VERSION 5.7 ;
  NOWIREEXTENSIONATPIN ON ;
  DIVIDERCHAR "/" ;
  BUSBITCHARS "[]" ;
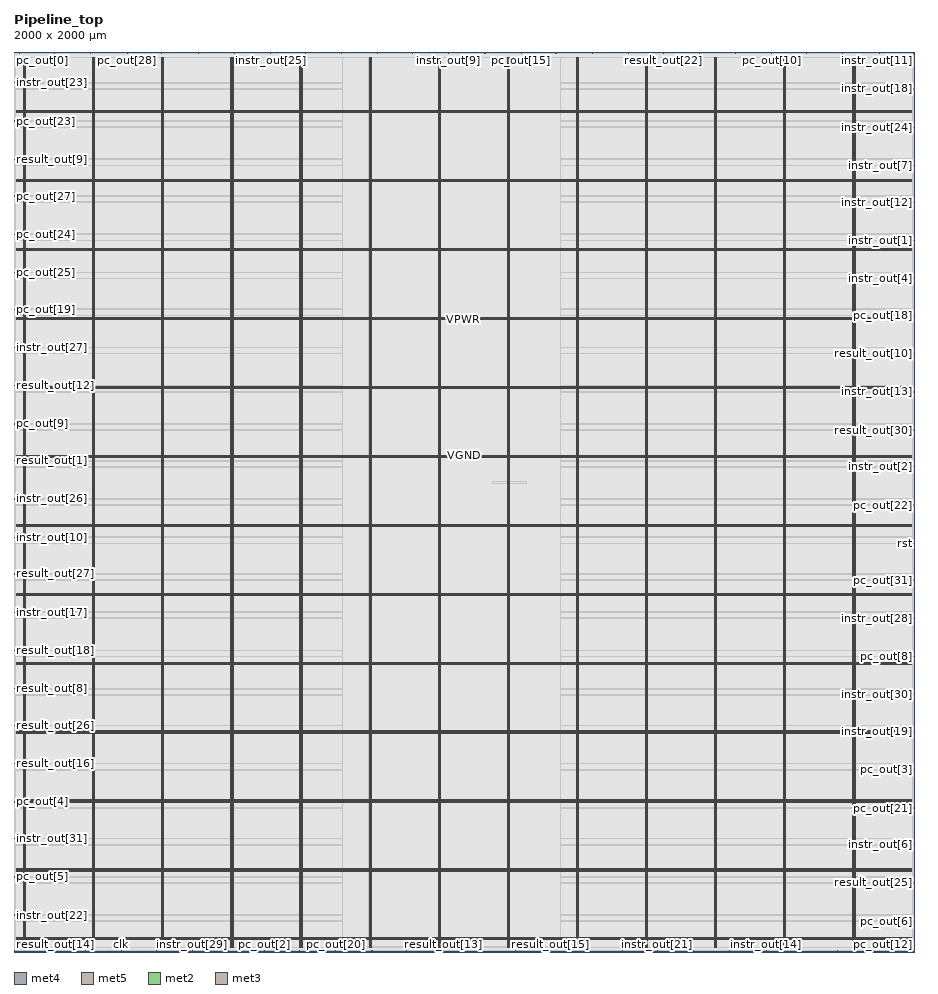
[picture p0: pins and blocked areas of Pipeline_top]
MACRO Pipeline_top
  CLASS BLOCK ;
  FOREIGN Pipeline_top ;
  ORIGIN 0.000 0.000 ;
  SIZE 2000.000 BY 2000.000 ;
  PIN VGND
    DIRECTION INOUT ;
    USE GROUND ;
    PORT
      LAYER met4 ;
        RECT 24.340 10.640 25.940 1988.560 ;
    END
    PORT
      LAYER met4 ;
        RECT 177.940 10.640 179.540 1988.560 ;
    END
    PORT
      LAYER met4 ;
        RECT 331.540 10.640 333.140 1988.560 ;
    END
    PORT
      LAYER met4 ;
        RECT 485.140 10.640 486.740 1988.560 ;
    END
    PORT
      LAYER met4 ;
        RECT 638.740 10.640 640.340 1988.560 ;
    END
    PORT
      LAYER met4 ;
        RECT 792.340 10.640 793.940 1988.560 ;
    END
    PORT
      LAYER met4 ;
        RECT 945.940 10.640 947.540 1988.560 ;
    END
    PORT
      LAYER met4 ;
        RECT 1099.540 10.640 1101.140 1988.560 ;
    END
    PORT
      LAYER met4 ;
        RECT 1253.140 10.640 1254.740 1988.560 ;
    END
    PORT
      LAYER met4 ;
        RECT 1406.740 10.640 1408.340 1988.560 ;
    END
    PORT
      LAYER met4 ;
        RECT 1560.340 10.640 1561.940 1988.560 ;
    END
    PORT
      LAYER met4 ;
        RECT 1713.940 10.640 1715.540 1988.560 ;
    END
    PORT
      LAYER met4 ;
        RECT 1867.540 10.640 1869.140 1988.560 ;
    END
    PORT
      LAYER met5 ;
        RECT 5.280 30.030 1994.340 31.630 ;
    END
    PORT
      LAYER met5 ;
        RECT 5.280 183.210 1994.340 184.810 ;
    END
    PORT
      LAYER met5 ;
        RECT 5.280 336.390 1994.340 337.990 ;
    END
    PORT
      LAYER met5 ;
        RECT 5.280 489.570 1994.340 491.170 ;
    END
    PORT
      LAYER met5 ;
        RECT 5.280 642.750 1994.340 644.350 ;
    END
    PORT
      LAYER met5 ;
        RECT 5.280 795.930 1994.340 797.530 ;
    END
    PORT
      LAYER met5 ;
        RECT 5.280 949.110 1994.340 950.710 ;
    END
    PORT
      LAYER met5 ;
        RECT 5.280 1102.290 1994.340 1103.890 ;
    END
    PORT
      LAYER met5 ;
        RECT 5.280 1255.470 1994.340 1257.070 ;
    END
    PORT
      LAYER met5 ;
        RECT 5.280 1408.650 1994.340 1410.250 ;
    END
    PORT
      LAYER met5 ;
        RECT 5.280 1561.830 1994.340 1563.430 ;
    END
    PORT
      LAYER met5 ;
        RECT 5.280 1715.010 1994.340 1716.610 ;
    END
    PORT
      LAYER met5 ;
        RECT 5.280 1868.190 1994.340 1869.790 ;
    END
  END VGND
  PIN VPWR
    DIRECTION INOUT ;
    USE POWER ;
    PORT
      LAYER met4 ;
        RECT 21.040 10.640 22.640 1988.560 ;
    END
    PORT
      LAYER met4 ;
        RECT 174.640 10.640 176.240 1988.560 ;
    END
    PORT
      LAYER met4 ;
        RECT 328.240 10.640 329.840 1988.560 ;
    END
    PORT
      LAYER met4 ;
        RECT 481.840 10.640 483.440 1988.560 ;
    END
    PORT
      LAYER met4 ;
        RECT 635.440 10.640 637.040 1988.560 ;
    END
    PORT
      LAYER met4 ;
        RECT 789.040 10.640 790.640 1988.560 ;
    END
    PORT
      LAYER met4 ;
        RECT 942.640 10.640 944.240 1988.560 ;
    END
    PORT
      LAYER met4 ;
        RECT 1096.240 10.640 1097.840 1988.560 ;
    END
    PORT
      LAYER met4 ;
        RECT 1249.840 10.640 1251.440 1988.560 ;
    END
    PORT
      LAYER met4 ;
        RECT 1403.440 10.640 1405.040 1988.560 ;
    END
    PORT
      LAYER met4 ;
        RECT 1557.040 10.640 1558.640 1988.560 ;
    END
    PORT
      LAYER met4 ;
        RECT 1710.640 10.640 1712.240 1988.560 ;
    END
    PORT
      LAYER met4 ;
        RECT 1864.240 10.640 1865.840 1988.560 ;
    END
    PORT
      LAYER met5 ;
        RECT 5.280 26.730 1994.340 28.330 ;
    END
    PORT
      LAYER met5 ;
        RECT 5.280 179.910 1994.340 181.510 ;
    END
    PORT
      LAYER met5 ;
        RECT 5.280 333.090 1994.340 334.690 ;
    END
    PORT
      LAYER met5 ;
        RECT 5.280 486.270 1994.340 487.870 ;
    END
    PORT
      LAYER met5 ;
        RECT 5.280 639.450 1994.340 641.050 ;
    END
    PORT
      LAYER met5 ;
        RECT 5.280 792.630 1994.340 794.230 ;
    END
    PORT
      LAYER met5 ;
        RECT 5.280 945.810 1994.340 947.410 ;
    END
    PORT
      LAYER met5 ;
        RECT 5.280 1098.990 1994.340 1100.590 ;
    END
    PORT
      LAYER met5 ;
        RECT 5.280 1252.170 1994.340 1253.770 ;
    END
    PORT
      LAYER met5 ;
        RECT 5.280 1405.350 1994.340 1406.950 ;
    END
    PORT
      LAYER met5 ;
        RECT 5.280 1558.530 1994.340 1560.130 ;
    END
    PORT
      LAYER met5 ;
        RECT 5.280 1711.710 1994.340 1713.310 ;
    END
    PORT
      LAYER met5 ;
        RECT 5.280 1864.890 1994.340 1866.490 ;
    END
  END VPWR
  PIN clk
    DIRECTION INPUT ;
    USE SIGNAL ;
    ANTENNAGATEAREA 1.286700 ;
    ANTENNADIFFAREA 0.434700 ;
    PORT
      LAYER met2 ;
        RECT 238.370 0.000 238.650 4.000 ;
    END
  END clk
  PIN instr_out[0]
    DIRECTION OUTPUT TRISTATE ;
    USE SIGNAL ;
    ANTENNADIFFAREA 0.795200 ;
    PORT
      LAYER met2 ;
        RECT 1365.370 1996.000 1365.650 2000.000 ;
    END
  END instr_out[0]
  PIN instr_out[10]
    DIRECTION OUTPUT TRISTATE ;
    USE SIGNAL ;
    ANTENNADIFFAREA 0.795200 ;
    PORT
      LAYER met3 ;
        RECT 0.000 921.440 4.000 922.040 ;
    END
  END instr_out[10]
  PIN instr_out[11]
    DIRECTION OUTPUT TRISTATE ;
    USE SIGNAL ;
    PORT
      LAYER met2 ;
        RECT 1922.430 1996.000 1922.710 2000.000 ;
    END
  END instr_out[11]
  PIN instr_out[12]
    DIRECTION OUTPUT TRISTATE ;
    USE SIGNAL ;
    PORT
      LAYER met3 ;
        RECT 1996.000 1666.040 2000.000 1666.640 ;
    END
  END instr_out[12]
  PIN instr_out[13]
    DIRECTION OUTPUT TRISTATE ;
    USE SIGNAL ;
    ANTENNADIFFAREA 0.445500 ;
    PORT
      LAYER met3 ;
        RECT 1996.000 1244.440 2000.000 1245.040 ;
    END
  END instr_out[13]
  PIN instr_out[14]
    DIRECTION OUTPUT TRISTATE ;
    USE SIGNAL ;
    PORT
      LAYER met2 ;
        RECT 1671.270 0.000 1671.550 4.000 ;
    END
  END instr_out[14]
  PIN instr_out[15]
    DIRECTION OUTPUT TRISTATE ;
    USE SIGNAL ;
    ANTENNADIFFAREA 0.795200 ;
    PORT
      LAYER met2 ;
        RECT 727.810 1996.000 728.090 2000.000 ;
    END
  END instr_out[15]
  PIN instr_out[16]
    DIRECTION OUTPUT TRISTATE ;
    USE SIGNAL ;
    PORT
      LAYER met2 ;
        RECT 808.310 1996.000 808.590 2000.000 ;
    END
  END instr_out[16]
  PIN instr_out[17]
    DIRECTION OUTPUT TRISTATE ;
    USE SIGNAL ;
    ANTENNADIFFAREA 0.795200 ;
    PORT
      LAYER met3 ;
        RECT 0.000 754.840 4.000 755.440 ;
    END
  END instr_out[17]
  PIN instr_out[18]
    DIRECTION OUTPUT TRISTATE ;
    USE SIGNAL ;
    ANTENNADIFFAREA 0.795200 ;
    PORT
      LAYER met3 ;
        RECT 1996.000 1917.640 2000.000 1918.240 ;
    END
  END instr_out[18]
  PIN instr_out[19]
    DIRECTION OUTPUT TRISTATE ;
    USE SIGNAL ;
    PORT
      LAYER met3 ;
        RECT 1996.000 489.640 2000.000 490.240 ;
    END
  END instr_out[19]
  PIN instr_out[1]
    DIRECTION OUTPUT TRISTATE ;
    USE SIGNAL ;
    ANTENNADIFFAREA 0.445500 ;
    PORT
      LAYER met3 ;
        RECT 1996.000 1581.040 2000.000 1581.640 ;
    END
  END instr_out[1]
  PIN instr_out[20]
    DIRECTION OUTPUT TRISTATE ;
    USE SIGNAL ;
    ANTENNADIFFAREA 0.795200 ;
    PORT
      LAYER met2 ;
        RECT 647.310 1996.000 647.590 2000.000 ;
    END
  END instr_out[20]
  PIN instr_out[21]
    DIRECTION OUTPUT TRISTATE ;
    USE SIGNAL ;
    ANTENNADIFFAREA 0.795200 ;
    PORT
      LAYER met2 ;
        RECT 1429.770 0.000 1430.050 4.000 ;
    END
  END instr_out[21]
  PIN instr_out[22]
    DIRECTION OUTPUT TRISTATE ;
    USE SIGNAL ;
    ANTENNADIFFAREA 0.795200 ;
    PORT
      LAYER met3 ;
        RECT 0.000 81.640 4.000 82.240 ;
    END
  END instr_out[22]
  PIN instr_out[23]
    DIRECTION OUTPUT TRISTATE ;
    USE SIGNAL ;
    ANTENNADIFFAREA 0.795200 ;
    PORT
      LAYER met3 ;
        RECT 0.000 1931.240 4.000 1931.840 ;
    END
  END instr_out[23]
  PIN instr_out[24]
    DIRECTION OUTPUT TRISTATE ;
    USE SIGNAL ;
    PORT
      LAYER met3 ;
        RECT 1996.000 1832.640 2000.000 1833.240 ;
    END
  END instr_out[24]
  PIN instr_out[25]
    DIRECTION OUTPUT TRISTATE ;
    USE SIGNAL ;
    PORT
      LAYER met2 ;
        RECT 570.030 1996.000 570.310 2000.000 ;
    END
  END instr_out[25]
  PIN instr_out[26]
    DIRECTION OUTPUT TRISTATE ;
    USE SIGNAL ;
    PORT
      LAYER met3 ;
        RECT 0.000 1006.440 4.000 1007.040 ;
    END
  END instr_out[26]
  PIN instr_out[27]
    DIRECTION OUTPUT TRISTATE ;
    USE SIGNAL ;
    PORT
      LAYER met3 ;
        RECT 0.000 1343.040 4.000 1343.640 ;
    END
  END instr_out[27]
  PIN instr_out[28]
    DIRECTION OUTPUT TRISTATE ;
    USE SIGNAL ;
    PORT
      LAYER met3 ;
        RECT 1996.000 741.240 2000.000 741.840 ;
    END
  END instr_out[28]
  PIN instr_out[29]
    DIRECTION OUTPUT TRISTATE ;
    USE SIGNAL ;
    PORT
      LAYER met2 ;
        RECT 396.150 0.000 396.430 4.000 ;
    END
  END instr_out[29]
  PIN instr_out[2]
    DIRECTION OUTPUT TRISTATE ;
    USE SIGNAL ;
    PORT
      LAYER met3 ;
        RECT 1996.000 1077.840 2000.000 1078.440 ;
    END
  END instr_out[2]
  PIN instr_out[30]
    DIRECTION OUTPUT TRISTATE ;
    USE SIGNAL ;
    PORT
      LAYER met3 ;
        RECT 1996.000 571.240 2000.000 571.840 ;
    END
  END instr_out[30]
  PIN instr_out[31]
    DIRECTION OUTPUT TRISTATE ;
    USE SIGNAL ;
    PORT
      LAYER met3 ;
        RECT 0.000 251.640 4.000 252.240 ;
    END
  END instr_out[31]
  PIN instr_out[3]
    DIRECTION OUTPUT TRISTATE ;
    USE SIGNAL ;
    PORT
      LAYER met2 ;
        RECT 795.430 0.000 795.710 4.000 ;
    END
  END instr_out[3]
  PIN instr_out[4]
    DIRECTION OUTPUT TRISTATE ;
    USE SIGNAL ;
    ANTENNADIFFAREA 0.445500 ;
    PORT
      LAYER met3 ;
        RECT 1996.000 1496.040 2000.000 1496.640 ;
    END
  END instr_out[4]
  PIN instr_out[5]
    DIRECTION OUTPUT TRISTATE ;
    USE SIGNAL ;
    ANTENNADIFFAREA 0.795200 ;
    PORT
      LAYER met2 ;
        RECT 1271.990 0.000 1272.270 4.000 ;
    END
  END instr_out[5]
  PIN instr_out[6]
    DIRECTION OUTPUT TRISTATE ;
    USE SIGNAL ;
    PORT
      LAYER met3 ;
        RECT 1996.000 238.040 2000.000 238.640 ;
    END
  END instr_out[6]
  PIN instr_out[7]
    DIRECTION OUTPUT TRISTATE ;
    USE SIGNAL ;
    ANTENNADIFFAREA 0.445500 ;
    PORT
      LAYER met3 ;
        RECT 1996.000 1747.640 2000.000 1748.240 ;
    END
  END instr_out[7]
  PIN instr_out[8]
    DIRECTION OUTPUT TRISTATE ;
    USE SIGNAL ;
    ANTENNADIFFAREA 0.795200 ;
    PORT
      LAYER met2 ;
        RECT 1284.870 1996.000 1285.150 2000.000 ;
    END
  END instr_out[8]
  PIN instr_out[9]
    DIRECTION OUTPUT TRISTATE ;
    USE SIGNAL ;
    ANTENNADIFFAREA 0.795200 ;
    PORT
      LAYER met2 ;
        RECT 966.090 1996.000 966.370 2000.000 ;
    END
  END instr_out[9]
  PIN pc_out[0]
    DIRECTION OUTPUT TRISTATE ;
    USE SIGNAL ;
    PORT
      LAYER met2 ;
        RECT 12.970 1996.000 13.250 2000.000 ;
    END
  END pc_out[0]
  PIN pc_out[10]
    DIRECTION OUTPUT TRISTATE ;
    USE SIGNAL ;
    ANTENNADIFFAREA 0.795200 ;
    PORT
      LAYER met2 ;
        RECT 1684.150 1996.000 1684.430 2000.000 ;
    END
  END pc_out[10]
  PIN pc_out[11]
    DIRECTION OUTPUT TRISTATE ;
    USE SIGNAL ;
    ANTENNADIFFAREA 0.795200 ;
    PORT
      LAYER met2 ;
        RECT 476.650 0.000 476.930 4.000 ;
    END
  END pc_out[11]
  PIN pc_out[12]
    DIRECTION OUTPUT TRISTATE ;
    USE SIGNAL ;
    ANTENNADIFFAREA 0.795200 ;
    PORT
      LAYER met2 ;
        RECT 1986.830 0.000 1987.110 4.000 ;
    END
  END pc_out[12]
  PIN pc_out[13]
    DIRECTION OUTPUT TRISTATE ;
    USE SIGNAL ;
    ANTENNADIFFAREA 0.795200 ;
    PORT
      LAYER met2 ;
        RECT 1829.050 0.000 1829.330 4.000 ;
    END
  END pc_out[13]
  PIN pc_out[14]
    DIRECTION OUTPUT TRISTATE ;
    USE SIGNAL ;
    ANTENNADIFFAREA 0.795200 ;
    PORT
      LAYER met2 ;
        RECT 885.590 1996.000 885.870 2000.000 ;
    END
  END pc_out[14]
  PIN pc_out[15]
    DIRECTION OUTPUT TRISTATE ;
    USE SIGNAL ;
    ANTENNADIFFAREA 0.795200 ;
    PORT
      LAYER met2 ;
        RECT 1127.090 1996.000 1127.370 2000.000 ;
    END
  END pc_out[15]
  PIN pc_out[16]
    DIRECTION OUTPUT TRISTATE ;
    USE SIGNAL ;
    ANTENNADIFFAREA 0.795200 ;
    PORT
      LAYER met2 ;
        RECT 1761.430 1996.000 1761.710 2000.000 ;
    END
  END pc_out[16]
  PIN pc_out[17]
    DIRECTION OUTPUT TRISTATE ;
    USE SIGNAL ;
    ANTENNADIFFAREA 0.795200 ;
    PORT
      LAYER met2 ;
        RECT 1909.550 0.000 1909.830 4.000 ;
    END
  END pc_out[17]
  PIN pc_out[18]
    DIRECTION OUTPUT TRISTATE ;
    USE SIGNAL ;
    ANTENNADIFFAREA 0.795200 ;
    PORT
      LAYER met3 ;
        RECT 1996.000 1414.440 2000.000 1415.040 ;
    END
  END pc_out[18]
  PIN pc_out[19]
    DIRECTION OUTPUT TRISTATE ;
    USE SIGNAL ;
    ANTENNADIFFAREA 0.795200 ;
    PORT
      LAYER met3 ;
        RECT 0.000 1428.040 4.000 1428.640 ;
    END
  END pc_out[19]
  PIN pc_out[1]
    DIRECTION OUTPUT TRISTATE ;
    USE SIGNAL ;
    PORT
      LAYER met2 ;
        RECT 1204.370 1996.000 1204.650 2000.000 ;
    END
  END pc_out[1]
  PIN pc_out[20]
    DIRECTION OUTPUT TRISTATE ;
    USE SIGNAL ;
    ANTENNADIFFAREA 0.795200 ;
    PORT
      LAYER met2 ;
        RECT 714.930 0.000 715.210 4.000 ;
    END
  END pc_out[20]
  PIN pc_out[21]
    DIRECTION OUTPUT TRISTATE ;
    USE SIGNAL ;
    ANTENNADIFFAREA 0.445500 ;
    PORT
      LAYER met3 ;
        RECT 1996.000 319.640 2000.000 320.240 ;
    END
  END pc_out[21]
  PIN pc_out[22]
    DIRECTION OUTPUT TRISTATE ;
    USE SIGNAL ;
    ANTENNADIFFAREA 0.795200 ;
    PORT
      LAYER met3 ;
        RECT 1996.000 992.840 2000.000 993.440 ;
    END
  END pc_out[22]
  PIN pc_out[23]
    DIRECTION OUTPUT TRISTATE ;
    USE SIGNAL ;
    ANTENNADIFFAREA 0.795200 ;
    PORT
      LAYER met3 ;
        RECT 0.000 1846.240 4.000 1846.840 ;
    END
  END pc_out[23]
  PIN pc_out[24]
    DIRECTION OUTPUT TRISTATE ;
    USE SIGNAL ;
    ANTENNADIFFAREA 0.795200 ;
    PORT
      LAYER met3 ;
        RECT 0.000 1594.640 4.000 1595.240 ;
    END
  END pc_out[24]
  PIN pc_out[25]
    DIRECTION OUTPUT TRISTATE ;
    USE SIGNAL ;
    ANTENNADIFFAREA 0.795200 ;
    PORT
      LAYER met3 ;
        RECT 0.000 1509.640 4.000 1510.240 ;
    END
  END pc_out[25]
  PIN pc_out[26]
    DIRECTION OUTPUT TRISTATE ;
    USE SIGNAL ;
    ANTENNADIFFAREA 0.795200 ;
    PORT
      LAYER met2 ;
        RECT 1510.270 0.000 1510.550 4.000 ;
    END
  END pc_out[26]
  PIN pc_out[27]
    DIRECTION OUTPUT TRISTATE ;
    USE SIGNAL ;
    ANTENNADIFFAREA 0.795200 ;
    PORT
      LAYER met3 ;
        RECT 0.000 1679.640 4.000 1680.240 ;
    END
  END pc_out[27]
  PIN pc_out[28]
    DIRECTION OUTPUT TRISTATE ;
    USE SIGNAL ;
    ANTENNADIFFAREA 0.795200 ;
    PORT
      LAYER met2 ;
        RECT 251.250 1996.000 251.530 2000.000 ;
    END
  END pc_out[28]
  PIN pc_out[29]
    DIRECTION OUTPUT TRISTATE ;
    USE SIGNAL ;
    ANTENNADIFFAREA 0.795200 ;
    PORT
      LAYER met2 ;
        RECT 157.870 0.000 158.150 4.000 ;
    END
  END pc_out[29]
  PIN pc_out[2]
    DIRECTION OUTPUT TRISTATE ;
    USE SIGNAL ;
    ANTENNADIFFAREA 0.795200 ;
    PORT
      LAYER met2 ;
        RECT 557.150 0.000 557.430 4.000 ;
    END
  END pc_out[2]
  PIN pc_out[30]
    DIRECTION OUTPUT TRISTATE ;
    USE SIGNAL ;
    ANTENNADIFFAREA 0.795200 ;
    PORT
      LAYER met2 ;
        RECT 1748.550 0.000 1748.830 4.000 ;
    END
  END pc_out[30]
  PIN pc_out[31]
    DIRECTION OUTPUT TRISTATE ;
    USE SIGNAL ;
    ANTENNADIFFAREA 0.795200 ;
    PORT
      LAYER met3 ;
        RECT 1996.000 826.240 2000.000 826.840 ;
    END
  END pc_out[31]
  PIN pc_out[3]
    DIRECTION OUTPUT TRISTATE ;
    USE SIGNAL ;
    ANTENNADIFFAREA 0.445500 ;
    PORT
      LAYER met3 ;
        RECT 1996.000 404.640 2000.000 405.240 ;
    END
  END pc_out[3]
  PIN pc_out[4]
    DIRECTION OUTPUT TRISTATE ;
    USE SIGNAL ;
    ANTENNADIFFAREA 0.795200 ;
    PORT
      LAYER met3 ;
        RECT 0.000 333.240 4.000 333.840 ;
    END
  END pc_out[4]
  PIN pc_out[5]
    DIRECTION OUTPUT TRISTATE ;
    USE SIGNAL ;
    ANTENNADIFFAREA 0.795200 ;
    PORT
      LAYER met3 ;
        RECT 0.000 166.640 4.000 167.240 ;
    END
  END pc_out[5]
  PIN pc_out[6]
    DIRECTION OUTPUT TRISTATE ;
    USE SIGNAL ;
    ANTENNADIFFAREA 0.795200 ;
    PORT
      LAYER met3 ;
        RECT 1996.000 68.040 2000.000 68.640 ;
    END
  END pc_out[6]
  PIN pc_out[7]
    DIRECTION OUTPUT TRISTATE ;
    USE SIGNAL ;
    ANTENNADIFFAREA 0.795200 ;
    PORT
      LAYER met2 ;
        RECT 328.530 1996.000 328.810 2000.000 ;
    END
  END pc_out[7]
  PIN pc_out[8]
    DIRECTION OUTPUT TRISTATE ;
    USE SIGNAL ;
    ANTENNADIFFAREA 0.445500 ;
    PORT
      LAYER met3 ;
        RECT 1996.000 656.240 2000.000 656.840 ;
    END
  END pc_out[8]
  PIN pc_out[9]
    DIRECTION OUTPUT TRISTATE ;
    USE SIGNAL ;
    ANTENNADIFFAREA 0.795200 ;
    PORT
      LAYER met3 ;
        RECT 0.000 1173.040 4.000 1173.640 ;
    END
  END pc_out[9]
  PIN result_out[0]
    DIRECTION OUTPUT TRISTATE ;
    USE SIGNAL ;
    ANTENNADIFFAREA 0.795200 ;
    PORT
      LAYER met2 ;
        RECT 1590.770 0.000 1591.050 4.000 ;
    END
  END result_out[0]
  PIN result_out[10]
    DIRECTION OUTPUT TRISTATE ;
    USE SIGNAL ;
    ANTENNADIFFAREA 0.445500 ;
    PORT
      LAYER met3 ;
        RECT 1996.000 1329.440 2000.000 1330.040 ;
    END
  END result_out[10]
  PIN result_out[11]
    DIRECTION OUTPUT TRISTATE ;
    USE SIGNAL ;
    ANTENNADIFFAREA 0.795200 ;
    PORT
      LAYER met2 ;
        RECT 409.030 1996.000 409.310 2000.000 ;
    END
  END result_out[11]
  PIN result_out[12]
    DIRECTION OUTPUT TRISTATE ;
    USE SIGNAL ;
    ANTENNADIFFAREA 0.795200 ;
    PORT
      LAYER met3 ;
        RECT 0.000 1258.040 4.000 1258.640 ;
    END
  END result_out[12]
  PIN result_out[13]
    DIRECTION OUTPUT TRISTATE ;
    USE SIGNAL ;
    ANTENNADIFFAREA 0.795200 ;
    PORT
      LAYER met2 ;
        RECT 953.210 0.000 953.490 4.000 ;
    END
  END result_out[13]
  PIN result_out[14]
    DIRECTION OUTPUT TRISTATE ;
    USE SIGNAL ;
    ANTENNADIFFAREA 0.795200 ;
    PORT
      LAYER met2 ;
        RECT 0.090 0.000 0.370 4.000 ;
    END
  END result_out[14]
  PIN result_out[15]
    DIRECTION OUTPUT TRISTATE ;
    USE SIGNAL ;
    ANTENNADIFFAREA 0.795200 ;
    PORT
      LAYER met2 ;
        RECT 1191.490 0.000 1191.770 4.000 ;
    END
  END result_out[15]
  PIN result_out[16]
    DIRECTION OUTPUT TRISTATE ;
    USE SIGNAL ;
    ANTENNADIFFAREA 0.795200 ;
    PORT
      LAYER met3 ;
        RECT 0.000 418.240 4.000 418.840 ;
    END
  END result_out[16]
  PIN result_out[17]
    DIRECTION OUTPUT TRISTATE ;
    USE SIGNAL ;
    ANTENNADIFFAREA 0.795200 ;
    PORT
      LAYER met2 ;
        RECT 1046.590 1996.000 1046.870 2000.000 ;
    END
  END result_out[17]
  PIN result_out[18]
    DIRECTION OUTPUT TRISTATE ;
    USE SIGNAL ;
    ANTENNADIFFAREA 0.795200 ;
    PORT
      LAYER met3 ;
        RECT 0.000 669.840 4.000 670.440 ;
    END
  END result_out[18]
  PIN result_out[19]
    DIRECTION OUTPUT TRISTATE ;
    USE SIGNAL ;
    ANTENNADIFFAREA 0.795200 ;
    PORT
      LAYER met2 ;
        RECT 90.250 1996.000 90.530 2000.000 ;
    END
  END result_out[19]
  PIN result_out[1]
    DIRECTION OUTPUT TRISTATE ;
    USE SIGNAL ;
    ANTENNADIFFAREA 0.795200 ;
    PORT
      LAYER met3 ;
        RECT 0.000 1091.440 4.000 1092.040 ;
    END
  END result_out[1]
  PIN result_out[20]
    DIRECTION OUTPUT TRISTATE ;
    USE SIGNAL ;
    ANTENNADIFFAREA 0.795200 ;
    PORT
      LAYER met2 ;
        RECT 77.370 0.000 77.650 4.000 ;
    END
  END result_out[20]
  PIN result_out[21]
    DIRECTION OUTPUT TRISTATE ;
    USE SIGNAL ;
    ANTENNADIFFAREA 0.795200 ;
    PORT
      LAYER met2 ;
        RECT 1841.930 1996.000 1842.210 2000.000 ;
    END
  END result_out[21]
  PIN result_out[22]
    DIRECTION OUTPUT TRISTATE ;
    USE SIGNAL ;
    ANTENNADIFFAREA 0.795200 ;
    PORT
      LAYER met2 ;
        RECT 1442.650 1996.000 1442.930 2000.000 ;
    END
  END result_out[22]
  PIN result_out[23]
    DIRECTION OUTPUT TRISTATE ;
    USE SIGNAL ;
    ANTENNADIFFAREA 0.795200 ;
    PORT
      LAYER met2 ;
        RECT 872.710 0.000 872.990 4.000 ;
    END
  END result_out[23]
  PIN result_out[24]
    DIRECTION OUTPUT TRISTATE ;
    USE SIGNAL ;
    ANTENNADIFFAREA 0.795200 ;
    PORT
      LAYER met2 ;
        RECT 1999.710 1996.000 1999.990 2000.000 ;
    END
  END result_out[24]
  PIN result_out[25]
    DIRECTION OUTPUT TRISTATE ;
    USE SIGNAL ;
    ANTENNADIFFAREA 0.445500 ;
    PORT
      LAYER met3 ;
        RECT 1996.000 153.040 2000.000 153.640 ;
    END
  END result_out[25]
  PIN result_out[26]
    DIRECTION OUTPUT TRISTATE ;
    USE SIGNAL ;
    ANTENNADIFFAREA 0.795200 ;
    PORT
      LAYER met3 ;
        RECT 0.000 503.240 4.000 503.840 ;
    END
  END result_out[26]
  PIN result_out[27]
    DIRECTION OUTPUT TRISTATE ;
    USE SIGNAL ;
    ANTENNADIFFAREA 0.795200 ;
    PORT
      LAYER met3 ;
        RECT 0.000 839.840 4.000 840.440 ;
    END
  END result_out[27]
  PIN result_out[28]
    DIRECTION OUTPUT TRISTATE ;
    USE SIGNAL ;
    ANTENNADIFFAREA 0.795200 ;
    PORT
      LAYER met2 ;
        RECT 315.650 0.000 315.930 4.000 ;
    END
  END result_out[28]
  PIN result_out[29]
    DIRECTION OUTPUT TRISTATE ;
    USE SIGNAL ;
    ANTENNADIFFAREA 0.795200 ;
    PORT
      LAYER met2 ;
        RECT 634.430 0.000 634.710 4.000 ;
    END
  END result_out[29]
  PIN result_out[2]
    DIRECTION OUTPUT TRISTATE ;
    USE SIGNAL ;
    ANTENNADIFFAREA 0.795200 ;
    PORT
      LAYER met2 ;
        RECT 1033.710 0.000 1033.990 4.000 ;
    END
  END result_out[2]
  PIN result_out[30]
    DIRECTION OUTPUT TRISTATE ;
    USE SIGNAL ;
    ANTENNADIFFAREA 0.795200 ;
    PORT
      LAYER met3 ;
        RECT 1996.000 1159.440 2000.000 1160.040 ;
    END
  END result_out[30]
  PIN result_out[31]
    DIRECTION OUTPUT TRISTATE ;
    USE SIGNAL ;
    ANTENNADIFFAREA 0.795200 ;
    PORT
      LAYER met2 ;
        RECT 1114.210 0.000 1114.490 4.000 ;
    END
  END result_out[31]
  PIN result_out[3]
    DIRECTION OUTPUT TRISTATE ;
    USE SIGNAL ;
    ANTENNADIFFAREA 0.795200 ;
    PORT
      LAYER met2 ;
        RECT 1603.650 1996.000 1603.930 2000.000 ;
    END
  END result_out[3]
  PIN result_out[4]
    DIRECTION OUTPUT TRISTATE ;
    USE SIGNAL ;
    ANTENNADIFFAREA 0.795200 ;
    PORT
      LAYER met2 ;
        RECT 1523.150 1996.000 1523.430 2000.000 ;
    END
  END result_out[4]
  PIN result_out[5]
    DIRECTION OUTPUT TRISTATE ;
    USE SIGNAL ;
    ANTENNADIFFAREA 0.795200 ;
    PORT
      LAYER met2 ;
        RECT 170.750 1996.000 171.030 2000.000 ;
    END
  END result_out[5]
  PIN result_out[6]
    DIRECTION OUTPUT TRISTATE ;
    USE SIGNAL ;
    ANTENNADIFFAREA 0.795200 ;
    PORT
      LAYER met2 ;
        RECT 489.530 1996.000 489.810 2000.000 ;
    END
  END result_out[6]
  PIN result_out[7]
    DIRECTION OUTPUT TRISTATE ;
    USE SIGNAL ;
    ANTENNADIFFAREA 0.795200 ;
    PORT
      LAYER met2 ;
        RECT 1352.490 0.000 1352.770 4.000 ;
    END
  END result_out[7]
  PIN result_out[8]
    DIRECTION OUTPUT TRISTATE ;
    USE SIGNAL ;
    ANTENNADIFFAREA 0.795200 ;
    PORT
      LAYER met3 ;
        RECT 0.000 584.840 4.000 585.440 ;
    END
  END result_out[8]
  PIN result_out[9]
    DIRECTION OUTPUT TRISTATE ;
    USE SIGNAL ;
    ANTENNADIFFAREA 0.795200 ;
    PORT
      LAYER met3 ;
        RECT 0.000 1761.240 4.000 1761.840 ;
    END
  END result_out[9]
  PIN rst
    DIRECTION INPUT ;
    USE SIGNAL ;
    ANTENNAGATEAREA 0.426000 ;
    PORT
      LAYER met3 ;
        RECT 1996.000 907.840 2000.000 908.440 ;
    END
  END rst
  OBS
      LAYER li1 ;
        RECT 5.520 10.795 1994.100 1988.405 ;
      LAYER met1 ;
        RECT 0.070 10.640 1999.550 1988.560 ;
      LAYER met2 ;
        RECT 0.100 1995.720 12.690 1996.210 ;
        RECT 13.530 1995.720 89.970 1996.210 ;
        RECT 90.810 1995.720 170.470 1996.210 ;
        RECT 171.310 1995.720 250.970 1996.210 ;
        RECT 251.810 1995.720 328.250 1996.210 ;
        RECT 329.090 1995.720 408.750 1996.210 ;
        RECT 409.590 1995.720 489.250 1996.210 ;
        RECT 490.090 1995.720 569.750 1996.210 ;
        RECT 570.590 1995.720 647.030 1996.210 ;
        RECT 647.870 1995.720 727.530 1996.210 ;
        RECT 728.370 1995.720 808.030 1996.210 ;
        RECT 808.870 1995.720 885.310 1996.210 ;
        RECT 886.150 1995.720 965.810 1996.210 ;
        RECT 966.650 1995.720 1046.310 1996.210 ;
        RECT 1047.150 1995.720 1126.810 1996.210 ;
        RECT 1127.650 1995.720 1204.090 1996.210 ;
        RECT 1204.930 1995.720 1284.590 1996.210 ;
        RECT 1285.430 1995.720 1365.090 1996.210 ;
        RECT 1365.930 1995.720 1442.370 1996.210 ;
        RECT 1443.210 1995.720 1522.870 1996.210 ;
        RECT 1523.710 1995.720 1603.370 1996.210 ;
        RECT 1604.210 1995.720 1683.870 1996.210 ;
        RECT 1684.710 1995.720 1761.150 1996.210 ;
        RECT 1761.990 1995.720 1841.650 1996.210 ;
        RECT 1842.490 1995.720 1922.150 1996.210 ;
        RECT 1922.990 1995.720 1999.430 1996.210 ;
        RECT 0.100 4.280 1999.920 1995.720 ;
        RECT 0.650 3.670 77.090 4.280 ;
        RECT 77.930 3.670 157.590 4.280 ;
        RECT 158.430 3.670 238.090 4.280 ;
        RECT 238.930 3.670 315.370 4.280 ;
        RECT 316.210 3.670 395.870 4.280 ;
        RECT 396.710 3.670 476.370 4.280 ;
        RECT 477.210 3.670 556.870 4.280 ;
        RECT 557.710 3.670 634.150 4.280 ;
        RECT 634.990 3.670 714.650 4.280 ;
        RECT 715.490 3.670 795.150 4.280 ;
        RECT 795.990 3.670 872.430 4.280 ;
        RECT 873.270 3.670 952.930 4.280 ;
        RECT 953.770 3.670 1033.430 4.280 ;
        RECT 1034.270 3.670 1113.930 4.280 ;
        RECT 1114.770 3.670 1191.210 4.280 ;
        RECT 1192.050 3.670 1271.710 4.280 ;
        RECT 1272.550 3.670 1352.210 4.280 ;
        RECT 1353.050 3.670 1429.490 4.280 ;
        RECT 1430.330 3.670 1509.990 4.280 ;
        RECT 1510.830 3.670 1590.490 4.280 ;
        RECT 1591.330 3.670 1670.990 4.280 ;
        RECT 1671.830 3.670 1748.270 4.280 ;
        RECT 1749.110 3.670 1828.770 4.280 ;
        RECT 1829.610 3.670 1909.270 4.280 ;
        RECT 1910.110 3.670 1986.550 4.280 ;
        RECT 1987.390 3.670 1999.920 4.280 ;
      LAYER met3 ;
        RECT 4.000 1932.240 1996.000 1988.485 ;
        RECT 4.400 1930.840 1996.000 1932.240 ;
        RECT 4.000 1918.640 1996.000 1930.840 ;
        RECT 4.000 1917.240 1995.600 1918.640 ;
        RECT 4.000 1847.240 1996.000 1917.240 ;
        RECT 4.400 1845.840 1996.000 1847.240 ;
        RECT 4.000 1833.640 1996.000 1845.840 ;
        RECT 4.000 1832.240 1995.600 1833.640 ;
        RECT 4.000 1762.240 1996.000 1832.240 ;
        RECT 4.400 1760.840 1996.000 1762.240 ;
        RECT 4.000 1748.640 1996.000 1760.840 ;
        RECT 4.000 1747.240 1995.600 1748.640 ;
        RECT 4.000 1680.640 1996.000 1747.240 ;
        RECT 4.400 1679.240 1996.000 1680.640 ;
        RECT 4.000 1667.040 1996.000 1679.240 ;
        RECT 4.000 1665.640 1995.600 1667.040 ;
        RECT 4.000 1595.640 1996.000 1665.640 ;
        RECT 4.400 1594.240 1996.000 1595.640 ;
        RECT 4.000 1582.040 1996.000 1594.240 ;
        RECT 4.000 1580.640 1995.600 1582.040 ;
        RECT 4.000 1510.640 1996.000 1580.640 ;
        RECT 4.400 1509.240 1996.000 1510.640 ;
        RECT 4.000 1497.040 1996.000 1509.240 ;
        RECT 4.000 1495.640 1995.600 1497.040 ;
        RECT 4.000 1429.040 1996.000 1495.640 ;
        RECT 4.400 1427.640 1996.000 1429.040 ;
        RECT 4.000 1415.440 1996.000 1427.640 ;
        RECT 4.000 1414.040 1995.600 1415.440 ;
        RECT 4.000 1344.040 1996.000 1414.040 ;
        RECT 4.400 1342.640 1996.000 1344.040 ;
        RECT 4.000 1330.440 1996.000 1342.640 ;
        RECT 4.000 1329.040 1995.600 1330.440 ;
        RECT 4.000 1259.040 1996.000 1329.040 ;
        RECT 4.400 1257.640 1996.000 1259.040 ;
        RECT 4.000 1245.440 1996.000 1257.640 ;
        RECT 4.000 1244.040 1995.600 1245.440 ;
        RECT 4.000 1174.040 1996.000 1244.040 ;
        RECT 4.400 1172.640 1996.000 1174.040 ;
        RECT 4.000 1160.440 1996.000 1172.640 ;
        RECT 4.000 1159.040 1995.600 1160.440 ;
        RECT 4.000 1092.440 1996.000 1159.040 ;
        RECT 4.400 1091.040 1996.000 1092.440 ;
        RECT 4.000 1078.840 1996.000 1091.040 ;
        RECT 4.000 1077.440 1995.600 1078.840 ;
        RECT 4.000 1007.440 1996.000 1077.440 ;
        RECT 4.400 1006.040 1996.000 1007.440 ;
        RECT 4.000 993.840 1996.000 1006.040 ;
        RECT 4.000 992.440 1995.600 993.840 ;
        RECT 4.000 922.440 1996.000 992.440 ;
        RECT 4.400 921.040 1996.000 922.440 ;
        RECT 4.000 908.840 1996.000 921.040 ;
        RECT 4.000 907.440 1995.600 908.840 ;
        RECT 4.000 840.840 1996.000 907.440 ;
        RECT 4.400 839.440 1996.000 840.840 ;
        RECT 4.000 827.240 1996.000 839.440 ;
        RECT 4.000 825.840 1995.600 827.240 ;
        RECT 4.000 755.840 1996.000 825.840 ;
        RECT 4.400 754.440 1996.000 755.840 ;
        RECT 4.000 742.240 1996.000 754.440 ;
        RECT 4.000 740.840 1995.600 742.240 ;
        RECT 4.000 670.840 1996.000 740.840 ;
        RECT 4.400 669.440 1996.000 670.840 ;
        RECT 4.000 657.240 1996.000 669.440 ;
        RECT 4.000 655.840 1995.600 657.240 ;
        RECT 4.000 585.840 1996.000 655.840 ;
        RECT 4.400 584.440 1996.000 585.840 ;
        RECT 4.000 572.240 1996.000 584.440 ;
        RECT 4.000 570.840 1995.600 572.240 ;
        RECT 4.000 504.240 1996.000 570.840 ;
        RECT 4.400 502.840 1996.000 504.240 ;
        RECT 4.000 490.640 1996.000 502.840 ;
        RECT 4.000 489.240 1995.600 490.640 ;
        RECT 4.000 419.240 1996.000 489.240 ;
        RECT 4.400 417.840 1996.000 419.240 ;
        RECT 4.000 405.640 1996.000 417.840 ;
        RECT 4.000 404.240 1995.600 405.640 ;
        RECT 4.000 334.240 1996.000 404.240 ;
        RECT 4.400 332.840 1996.000 334.240 ;
        RECT 4.000 320.640 1996.000 332.840 ;
        RECT 4.000 319.240 1995.600 320.640 ;
        RECT 4.000 252.640 1996.000 319.240 ;
        RECT 4.400 251.240 1996.000 252.640 ;
        RECT 4.000 239.040 1996.000 251.240 ;
        RECT 4.000 237.640 1995.600 239.040 ;
        RECT 4.000 167.640 1996.000 237.640 ;
        RECT 4.400 166.240 1996.000 167.640 ;
        RECT 4.000 154.040 1996.000 166.240 ;
        RECT 4.000 152.640 1995.600 154.040 ;
        RECT 4.000 82.640 1996.000 152.640 ;
        RECT 4.400 81.240 1996.000 82.640 ;
        RECT 4.000 69.040 1996.000 81.240 ;
        RECT 4.000 67.640 1995.600 69.040 ;
        RECT 4.000 10.715 1996.000 67.640 ;
      LAYER met4 ;
        RECT 730.775 11.735 788.640 1986.785 ;
        RECT 791.040 11.735 791.940 1986.785 ;
        RECT 794.340 11.735 942.240 1986.785 ;
        RECT 944.640 11.735 945.540 1986.785 ;
        RECT 947.940 11.735 1095.840 1986.785 ;
        RECT 1098.240 11.735 1099.140 1986.785 ;
        RECT 1101.540 11.735 1215.025 1986.785 ;
      LAYER met5 ;
        RECT 1062.260 1041.300 1139.300 1046.300 ;
  END
END Pipeline_top
END LIBRARY

